VERSION 5.7 ;
  NOWIREEXTENSIONATPIN ON ;
  DIVIDERCHAR "/" ;
  BUSBITCHARS "[]" ;
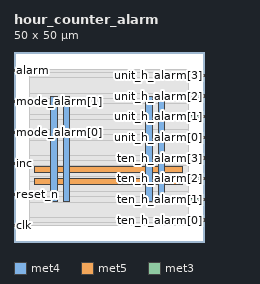
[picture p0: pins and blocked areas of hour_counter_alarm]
MACRO hour_counter_alarm
  CLASS BLOCK ;
  FOREIGN hour_counter_alarm ;
  ORIGIN 0.000 0.000 ;
  SIZE 50.000 BY 50.000 ;
  PIN VGND
    DIRECTION INOUT ;
    USE GROUND ;
    PORT
      LAYER met4 ;
        RECT 13.020 10.640 14.620 38.320 ;
    END
    PORT
      LAYER met4 ;
        RECT 38.020 10.640 39.620 38.320 ;
    END
    PORT
      LAYER met5 ;
        RECT 5.280 18.380 44.400 19.980 ;
    END
  END VGND
  PIN VPWR
    DIRECTION INOUT ;
    USE POWER ;
    PORT
      LAYER met4 ;
        RECT 9.720 10.640 11.320 38.320 ;
    END
    PORT
      LAYER met4 ;
        RECT 34.720 10.640 36.320 38.320 ;
    END
    PORT
      LAYER met5 ;
        RECT 5.280 15.080 44.400 16.680 ;
    END
  END VPWR
  PIN alarm
    DIRECTION INPUT ;
    USE SIGNAL ;
    ANTENNAGATEAREA 0.159000 ;
    PORT
      LAYER met3 ;
        RECT 0.000 44.920 4.000 45.520 ;
    END
  END alarm
  PIN clk
    DIRECTION INPUT ;
    USE SIGNAL ;
    ANTENNAGATEAREA 0.852000 ;
    PORT
      LAYER met3 ;
        RECT 0.000 4.120 4.000 4.720 ;
    END
  END clk
  PIN inc
    DIRECTION INPUT ;
    USE SIGNAL ;
    ANTENNAGATEAREA 0.196500 ;
    PORT
      LAYER met3 ;
        RECT 0.000 20.440 4.000 21.040 ;
    END
  END inc
  PIN mode_alarm[0]
    DIRECTION INPUT ;
    USE SIGNAL ;
    ANTENNAGATEAREA 0.196500 ;
    PORT
      LAYER met3 ;
        RECT 0.000 28.600 4.000 29.200 ;
    END
  END mode_alarm[0]
  PIN mode_alarm[1]
    DIRECTION INPUT ;
    USE SIGNAL ;
    ANTENNAGATEAREA 0.196500 ;
    PORT
      LAYER met3 ;
        RECT 0.000 36.760 4.000 37.360 ;
    END
  END mode_alarm[1]
  PIN reset_n
    DIRECTION INPUT ;
    USE SIGNAL ;
    ANTENNAGATEAREA 0.159000 ;
    PORT
      LAYER met3 ;
        RECT 0.000 12.280 4.000 12.880 ;
    END
  END reset_n
  PIN ten_h_alarm[0]
    DIRECTION OUTPUT ;
    USE SIGNAL ;
    ANTENNADIFFAREA 0.445500 ;
    PORT
      LAYER met3 ;
        RECT 46.000 5.480 50.000 6.080 ;
    END
  END ten_h_alarm[0]
  PIN ten_h_alarm[1]
    DIRECTION OUTPUT ;
    USE SIGNAL ;
    ANTENNADIFFAREA 0.445500 ;
    PORT
      LAYER met3 ;
        RECT 46.000 10.920 50.000 11.520 ;
    END
  END ten_h_alarm[1]
  PIN ten_h_alarm[2]
    DIRECTION OUTPUT ;
    USE SIGNAL ;
    ANTENNADIFFAREA 0.445500 ;
    PORT
      LAYER met3 ;
        RECT 46.000 16.360 50.000 16.960 ;
    END
  END ten_h_alarm[2]
  PIN ten_h_alarm[3]
    DIRECTION OUTPUT ;
    USE SIGNAL ;
    ANTENNADIFFAREA 0.445500 ;
    PORT
      LAYER met3 ;
        RECT 46.000 21.800 50.000 22.400 ;
    END
  END ten_h_alarm[3]
  PIN unit_h_alarm[0]
    DIRECTION OUTPUT ;
    USE SIGNAL ;
    ANTENNADIFFAREA 0.445500 ;
    PORT
      LAYER met3 ;
        RECT 46.000 27.240 50.000 27.840 ;
    END
  END unit_h_alarm[0]
  PIN unit_h_alarm[1]
    DIRECTION OUTPUT ;
    USE SIGNAL ;
    ANTENNADIFFAREA 0.445500 ;
    PORT
      LAYER met3 ;
        RECT 46.000 32.680 50.000 33.280 ;
    END
  END unit_h_alarm[1]
  PIN unit_h_alarm[2]
    DIRECTION OUTPUT ;
    USE SIGNAL ;
    ANTENNADIFFAREA 0.445500 ;
    PORT
      LAYER met3 ;
        RECT 46.000 38.120 50.000 38.720 ;
    END
  END unit_h_alarm[2]
  PIN unit_h_alarm[3]
    DIRECTION OUTPUT ;
    USE SIGNAL ;
    ANTENNADIFFAREA 0.445500 ;
    PORT
      LAYER met3 ;
        RECT 46.000 43.560 50.000 44.160 ;
    END
  END unit_h_alarm[3]
  OBS
      LAYER nwell ;
        RECT 5.330 10.795 44.350 38.165 ;
      LAYER li1 ;
        RECT 5.520 10.795 44.160 38.165 ;
      LAYER met1 ;
        RECT 4.210 10.640 44.160 38.320 ;
      LAYER met2 ;
        RECT 4.230 4.235 42.230 44.725 ;
      LAYER met3 ;
        RECT 4.400 44.560 46.000 45.370 ;
        RECT 4.400 44.520 45.600 44.560 ;
        RECT 3.990 43.160 45.600 44.520 ;
        RECT 3.990 39.120 46.000 43.160 ;
        RECT 3.990 37.760 45.600 39.120 ;
        RECT 4.400 37.720 45.600 37.760 ;
        RECT 4.400 36.360 46.000 37.720 ;
        RECT 3.990 33.680 46.000 36.360 ;
        RECT 3.990 32.280 45.600 33.680 ;
        RECT 3.990 29.600 46.000 32.280 ;
        RECT 4.400 28.240 46.000 29.600 ;
        RECT 4.400 28.200 45.600 28.240 ;
        RECT 3.990 26.840 45.600 28.200 ;
        RECT 3.990 22.800 46.000 26.840 ;
        RECT 3.990 21.440 45.600 22.800 ;
        RECT 4.400 21.400 45.600 21.440 ;
        RECT 4.400 20.040 46.000 21.400 ;
        RECT 3.990 17.360 46.000 20.040 ;
        RECT 3.990 15.960 45.600 17.360 ;
        RECT 3.990 13.280 46.000 15.960 ;
        RECT 4.400 11.920 46.000 13.280 ;
        RECT 4.400 11.880 45.600 11.920 ;
        RECT 3.990 10.520 45.600 11.880 ;
        RECT 3.990 6.480 46.000 10.520 ;
        RECT 3.990 5.120 45.600 6.480 ;
        RECT 4.400 5.080 45.600 5.120 ;
        RECT 4.400 4.255 46.000 5.080 ;
  END
END hour_counter_alarm
END LIBRARY

